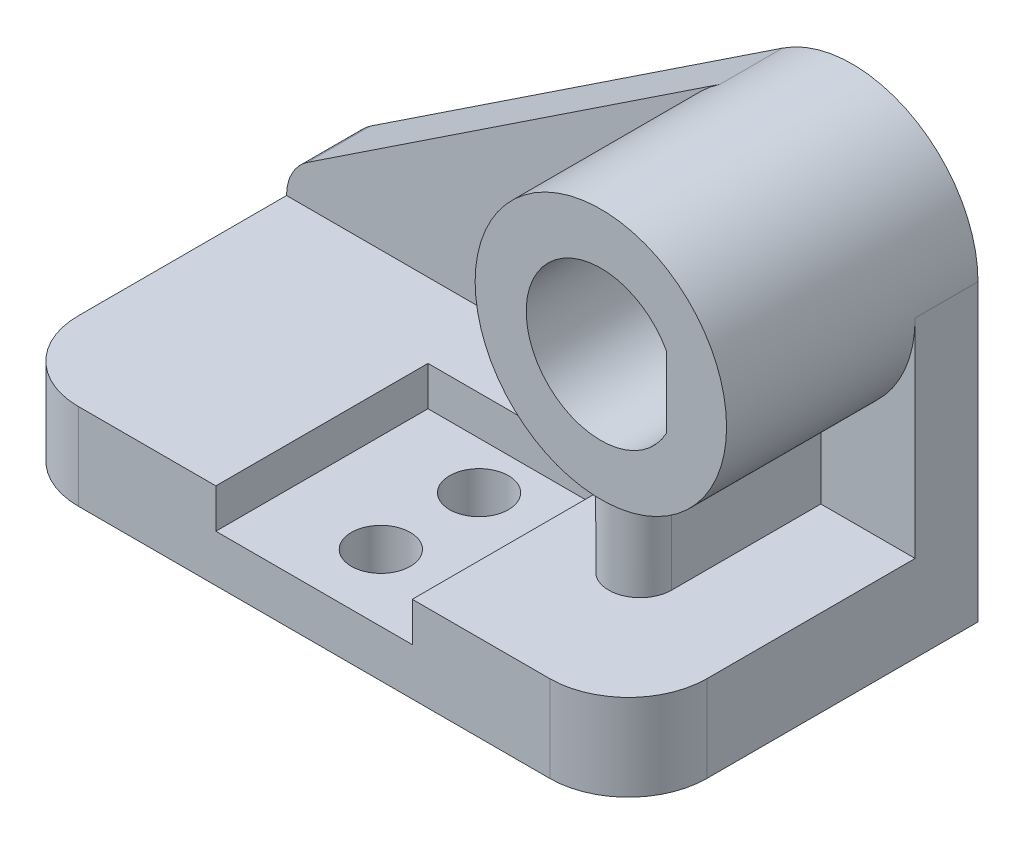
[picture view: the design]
ISO-10303-21;
HEADER;
FILE_DESCRIPTION(('STEP AP214'),'2;1');
FILE_NAME('part.step','',(''),(''),'','','');
FILE_SCHEMA(('AUTOMOTIVE_DESIGN { 1 0 10303 214 1 1 1 1 }'));
ENDSEC;
DATA;
#1=APPLICATION_CONTEXT('core data for automotive mechanical design processes');
#2=APPLICATION_PROTOCOL_DEFINITION('international standard','automotive_design',2000,#1);
#3=PRODUCT_CONTEXT('',#1,'mechanical');
#4=PRODUCT('Part','Part','',(#3));
#5=PRODUCT_RELATED_PRODUCT_CATEGORY('part','',(#4));
#6=PRODUCT_DEFINITION_FORMATION('','',#4);
#7=PRODUCT_DEFINITION_CONTEXT('part definition',#1,'design');
#8=PRODUCT_DEFINITION('design','',#6,#7);
#9=PRODUCT_DEFINITION_SHAPE('','',#8);
#10=(LENGTH_UNIT() NAMED_UNIT(*) SI_UNIT(.MILLI.,.METRE.));
#11=(NAMED_UNIT(*) PLANE_ANGLE_UNIT() SI_UNIT($,.RADIAN.));
#12=(NAMED_UNIT(*) SI_UNIT($,.STERADIAN.) SOLID_ANGLE_UNIT());
#13=UNCERTAINTY_MEASURE_WITH_UNIT(LENGTH_MEASURE(1.E-05),#10,'distance_accuracy_value','');
#14=(GEOMETRIC_REPRESENTATION_CONTEXT(3) GLOBAL_UNCERTAINTY_ASSIGNED_CONTEXT((#13)) GLOBAL_UNIT_ASSIGNED_CONTEXT((#10,
#11,#12)) REPRESENTATION_CONTEXT('',''));
#15=CARTESIAN_POINT('',(0.,0.,0.));
#16=DIRECTION('',(0.,0.,1.));
#17=DIRECTION('',(1.,0.,0.));
#18=AXIS2_PLACEMENT_3D('',#15,#16,#17);
#19=CARTESIAN_POINT('',(128.,75.,-73.));
#20=DIRECTION('',(0.,0.,-1.));
#21=DIRECTION('',(-1.,0.,0.));
#22=AXIS2_PLACEMENT_3D('',#19,#20,#21);
#23=CYLINDRICAL_SURFACE('',#22,32.);
#24=CARTESIAN_POINT('',(128.,75.,-25.));
#25=DIRECTION('',(0.,0.,-1.));
#26=DIRECTION('',(-1.,0.,0.));
#27=AXIS2_PLACEMENT_3D('',#24,#25,#26);
#28=CIRCLE('',#27,32.);
#29=CARTESIAN_POINT('',(96.,75.,-25.));
#30=VERTEX_POINT('',#29);
#31=EDGE_CURVE('E520',#30,#30,#28,.T.);
#32=ORIENTED_EDGE('',*,*,#31,.T.);
#33=EDGE_LOOP('',(#32));
#34=FACE_BOUND('',#33,.T.);
#35=CARTESIAN_POINT('',(128.,75.,-73.));
#36=DIRECTION('',(0.,0.,-1.));
#37=DIRECTION('',(-1.,0.,0.));
#38=AXIS2_PLACEMENT_3D('',#35,#36,#37);
#39=CIRCLE('',#38,32.);
#40=CARTESIAN_POINT('',(120.,44.0161332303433,-73.));
#41=VERTEX_POINT('',#40);
#42=CARTESIAN_POINT('',(110.301754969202,101.660309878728,-73.));
#43=VERTEX_POINT('',#42);
#44=EDGE_CURVE('E500',#41,#43,#39,.T.);
#45=ORIENTED_EDGE('',*,*,#44,.F.);
#46=DIRECTION('',(0.,0.,-1.));
#47=VECTOR('',#46,1.);
#48=CARTESIAN_POINT('',(120.,44.0161332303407,-73.));
#49=LINE('',#48,#47);
#50=CARTESIAN_POINT('',(120.,44.0161332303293,-35.));
#51=VERTEX_POINT('',#50);
#52=EDGE_CURVE('E446',#51,#41,#49,.T.);
#53=ORIENTED_EDGE('',*,*,#52,.F.);
#54=CARTESIAN_POINT('',(136.,44.0161332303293,-35.));
#55=CARTESIAN_POINT('',(136.000028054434,44.0161587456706,-34.7787632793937));
#56=CARTESIAN_POINT('',(135.990823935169,44.0137645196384,-34.5575354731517));
#57=CARTESIAN_POINT('',(135.954157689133,44.0043223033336,-34.1167341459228));
#58=CARTESIAN_POINT('',(135.926698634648,43.9972750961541,-33.897160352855));
#59=CARTESIAN_POINT('',(135.853800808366,43.9787308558,-33.4616585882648));
#60=CARTESIAN_POINT('',(135.808397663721,43.9672426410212,-33.2457242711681));
#61=CARTESIAN_POINT('',(135.699997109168,43.9401676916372,-32.8185811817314));
#62=CARTESIAN_POINT('',(135.636999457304,43.9245809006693,-32.6073724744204));
#63=CARTESIAN_POINT('',(135.493935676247,43.8897712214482,-32.1912044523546));
#64=CARTESIAN_POINT('',(135.413874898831,43.8705494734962,-31.9862432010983));
#65=CARTESIAN_POINT('',(135.237254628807,43.8290139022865,-31.5837954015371));
#66=CARTESIAN_POINT('',(135.140689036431,43.8066989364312,-31.3863116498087));
#67=CARTESIAN_POINT('',(134.931780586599,43.7596114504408,-31.0001741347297));
#68=CARTESIAN_POINT('',(134.81943714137,43.7348388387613,-30.8115207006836));
#69=CARTESIAN_POINT('',(134.579753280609,43.6835209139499,-30.4442414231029));
#70=CARTESIAN_POINT('',(134.452412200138,43.6569755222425,-30.2656160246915));
#71=CARTESIAN_POINT('',(134.180936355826,43.6022999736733,-29.9161090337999));
#72=CARTESIAN_POINT('',(134.036520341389,43.5741489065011,-29.7454491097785));
#73=CARTESIAN_POINT('',(133.733946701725,43.5175360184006,-29.416834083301));
#74=CARTESIAN_POINT('',(133.575788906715,43.4890741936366,-29.2588791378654));
#75=CARTESIAN_POINT('',(133.246739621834,43.4326183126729,-28.956687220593));
#76=CARTESIAN_POINT('',(133.075845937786,43.4046243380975,-28.8124526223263));
#77=CARTESIAN_POINT('',(132.722465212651,43.349877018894,-28.5387095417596));
#78=CARTESIAN_POINT('',(132.539978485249,43.3231236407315,-28.4092006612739));
#79=CARTESIAN_POINT('',(132.161932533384,43.2712239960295,-28.1640813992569));
#80=CARTESIAN_POINT('',(131.966224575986,43.2461059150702,-28.0486942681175));
#81=CARTESIAN_POINT('',(131.56551345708,43.1986195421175,-27.8348995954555));
#82=CARTESIAN_POINT('',(131.360513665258,43.1762502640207,-27.7364859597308));
#83=CARTESIAN_POINT('',(130.942582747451,43.1348890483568,-27.5573596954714));
#84=CARTESIAN_POINT('',(130.729651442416,43.1158971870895,-27.4766474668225));
#85=CARTESIAN_POINT('',(130.297399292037,43.0818398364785,-27.3335941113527));
#86=CARTESIAN_POINT('',(130.078078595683,43.0667742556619,-27.2712525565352));
#87=CARTESIAN_POINT('',(129.639162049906,43.0412689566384,-27.1665450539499));
#88=CARTESIAN_POINT('',(129.419661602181,43.0307417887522,-27.1238003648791));
#89=CARTESIAN_POINT('',(128.977688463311,43.0141746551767,-27.0568218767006));
#90=CARTESIAN_POINT('',(128.755215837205,43.0081345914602,-27.0325876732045));
#91=CARTESIAN_POINT('',(128.308967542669,43.0007135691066,-27.0028417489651));
#92=CARTESIAN_POINT('',(128.085192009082,42.9993321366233,-26.9973281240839));
#93=CARTESIAN_POINT('',(127.637987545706,43.0012665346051,-27.0050667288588));
#94=CARTESIAN_POINT('',(127.414558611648,43.0045823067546,-27.0183187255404));
#95=CARTESIAN_POINT('',(126.974700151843,43.015690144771,-27.0629646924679));
#96=CARTESIAN_POINT('',(126.758225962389,43.0233802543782,-27.0939455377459));
#97=CARTESIAN_POINT('',(126.328649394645,43.04295330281,-27.1734861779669));
#98=CARTESIAN_POINT('',(126.115548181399,43.0548376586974,-27.2220519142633));
#99=CARTESIAN_POINT('',(125.694337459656,43.0824741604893,-27.3363503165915));
#100=CARTESIAN_POINT('',(125.486226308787,43.0982250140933,-27.4020772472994));
#101=CARTESIAN_POINT('',(125.076246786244,43.1331831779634,-27.5502218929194));
#102=CARTESIAN_POINT('',(124.874380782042,43.152391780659,-27.6326458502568));
#103=CARTESIAN_POINT('',(124.476575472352,43.1939341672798,-27.8143399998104));
#104=CARTESIAN_POINT('',(124.280702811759,43.2162936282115,-27.9137501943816));
#105=CARTESIAN_POINT('',(123.897943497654,43.2634227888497,-28.1282260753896));
#106=CARTESIAN_POINT('',(123.71105996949,43.2881933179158,-28.2432971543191));
#107=CARTESIAN_POINT('',(123.347545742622,43.3394825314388,-28.4882640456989));
#108=CARTESIAN_POINT('',(123.170914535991,43.3660011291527,-28.6181591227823));
#109=CARTESIAN_POINT('',(122.828998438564,43.4200901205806,-28.8919145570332));
#110=CARTESIAN_POINT('',(122.663713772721,43.4476605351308,-29.0357751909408));
#111=CARTESIAN_POINT('',(122.34120003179,43.5038811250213,-29.3406231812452));
#112=CARTESIAN_POINT('',(122.184311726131,43.5325402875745,-29.5019696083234));
#113=CARTESIAN_POINT('',(121.884694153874,43.5893921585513,-29.8372902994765));
#114=CARTESIAN_POINT('',(121.741960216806,43.6175850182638,-30.0112603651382));
#115=CARTESIAN_POINT('',(121.471476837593,43.6727362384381,-30.3708496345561));
#116=CARTESIAN_POINT('',(121.343737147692,43.6996937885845,-30.5564763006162));
#117=CARTESIAN_POINT('',(121.104301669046,43.7515704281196,-30.9379756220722));
#118=CARTESIAN_POINT('',(120.99259970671,43.7764903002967,-31.1338442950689));
#119=CARTESIAN_POINT('',(120.78540787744,43.8237105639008,-31.5357441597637));
#120=CARTESIAN_POINT('',(120.690016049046,43.84599488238,-31.7418278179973));
#121=CARTESIAN_POINT('',(120.517029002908,43.8870918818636,-32.1615760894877));
#122=CARTESIAN_POINT('',(120.439426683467,43.9059059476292,-32.3752376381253));
#123=CARTESIAN_POINT('',(120.302684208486,43.9394737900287,-32.8084546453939));
#124=CARTESIAN_POINT('',(120.243524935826,43.9542317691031,-33.0280037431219));
#125=CARTESIAN_POINT('',(120.144091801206,43.979243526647,-33.4714978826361));
#126=CARTESIAN_POINT('',(120.103809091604,43.989499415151,-33.6954408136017));
#127=CARTESIAN_POINT('',(120.048780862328,44.0035684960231,-34.0996119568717));
#128=CARTESIAN_POINT('',(120.030482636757,44.0082740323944,-34.2793341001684));
#129=CARTESIAN_POINT('',(120.006096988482,44.0145591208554,-34.6393658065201));
#130=CARTESIAN_POINT('',(119.99998980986,44.0161437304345,-34.8196739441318));
#131=CARTESIAN_POINT('',(120.,44.0161332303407,-34.9999999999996));
#132=B_SPLINE_CURVE_WITH_KNOTS('',3,(#54,#55,#56,#57,#58,#59,#60,#61,#62,#63,#64,#65,#66,#67,
#68,#69,#70,#71,#72,#73,#74,#75,#76,#77,#78,#79,#80,#81,#82,#83,#84,#85,#86,#87,#88,#89,#90,#91,
#92,#93,#94,#95,#96,#97,#98,#99,#100,#101,#102,#103,#104,#105,#106,#107,#108,#109,#110,#111,
#112,#113,#114,#115,#116,#117,#118,#119,#120,#121,#122,#123,#124,#125,#126,#127,#128,#129,#130,
#131),.UNSPECIFIED.,.F.,.F.,(4,2,2,2,2,2,2,2,2,2,2,2,2,2,2,2,2,2,2,2,2,2,2,2,2,2,2,2,2,2,2,2,2,
2,2,2,2,2,4),(0.,0.66349224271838,1.32687284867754,1.98894290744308,2.65102207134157,
3.31289388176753,3.97501083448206,4.63715245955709,5.29932345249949,5.97452992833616,
6.64974474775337,7.3250761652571,8.00038931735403,8.68528336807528,9.36993099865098,
10.0545940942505,10.7392412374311,11.4100321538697,12.0808084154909,12.7515164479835,
13.4222161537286,14.0778887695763,14.7337831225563,15.3894585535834,16.0453795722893,
16.7069934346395,17.3688356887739,18.0306451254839,18.6924676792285,19.372267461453,
20.0518421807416,20.7318564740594,21.4116082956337,22.0953124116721,22.7787431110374,
23.4614630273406,24.143862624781,24.6855747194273,25.2264082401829),.UNSPECIFIED.);
#133=CARTESIAN_POINT('',(136.,44.0161332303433,-35.));
#134=VERTEX_POINT('',#133);
#135=EDGE_CURVE('E438',#134,#51,#132,.T.);
#136=ORIENTED_EDGE('',*,*,#135,.F.);
#137=DIRECTION('',(0.,0.,-1.));
#138=VECTOR('',#137,1.);
#139=CARTESIAN_POINT('',(136.,44.0161332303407,-73.));
#140=LINE('',#139,#138);
#141=CARTESIAN_POINT('',(136.,44.0161332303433,-73.));
#142=VERTEX_POINT('',#141);
#143=EDGE_CURVE('E436',#142,#134,#140,.F.);
#144=ORIENTED_EDGE('',*,*,#143,.F.);
#145=CARTESIAN_POINT('',(160.,75.,-73.));
#146=VERTEX_POINT('',#145);
#147=EDGE_CURVE('E497',#146,#142,#39,.T.);
#148=ORIENTED_EDGE('',*,*,#147,.F.);
#149=DIRECTION('',(0.,0.,-1.));
#150=VECTOR('',#149,1.);
#151=CARTESIAN_POINT('',(160.,75.,-73.));
#152=LINE('',#151,#150);
#153=CARTESIAN_POINT('',(160.,75.,-89.));
#154=VERTEX_POINT('',#153);
#155=EDGE_CURVE('E11',#146,#154,#152,.T.);
#156=ORIENTED_EDGE('',*,*,#155,.T.);
#157=CARTESIAN_POINT('',(128.,75.,-89.));
#158=DIRECTION('',(0.,0.,-1.));
#159=DIRECTION('',(-1.,0.,0.));
#160=AXIS2_PLACEMENT_3D('',#157,#158,#159);
#161=CIRCLE('',#160,32.);
#162=CARTESIAN_POINT('',(110.301754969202,101.660309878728,-89.));
#163=VERTEX_POINT('',#162);
#164=EDGE_CURVE('E492',#163,#154,#161,.T.);
#165=ORIENTED_EDGE('',*,*,#164,.F.);
#166=DIRECTION('',(0.,0.,-1.));
#167=VECTOR('',#166,1.);
#168=CARTESIAN_POINT('',(110.301754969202,101.660309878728,-73.));
#169=LINE('',#168,#167);
#170=EDGE_CURVE('E43',#43,#163,#169,.T.);
#171=ORIENTED_EDGE('',*,*,#170,.F.);
#172=EDGE_LOOP('',(#45,#53,#136,#144,#148,#156,#165,#171));
#173=FACE_BOUND('',#172,.T.);
#174=ADVANCED_FACE('F34',(#34,#173),#23,.T.);
#175=CARTESIAN_POINT('',(12.,22.,-73.));
#176=DIRECTION('',(0.,0.,-1.));
#177=DIRECTION('',(-1.,0.,0.));
#178=AXIS2_PLACEMENT_3D('',#175,#176,#177);
#179=PLANE('',#178);
#180=DIRECTION('',(0.,-1.,0.));
#181=VECTOR('',#180,1.);
#182=CARTESIAN_POINT('',(120.,500000.,-73.));
#183=LINE('',#182,#181);
#184=CARTESIAN_POINT('',(120.,22.,-73.));
#185=VERTEX_POINT('',#184);
#186=EDGE_CURVE('E434',#41,#185,#183,.T.);
#187=ORIENTED_EDGE('',*,*,#186,.F.);
#188=ORIENTED_EDGE('',*,*,#44,.T.);
#189=DIRECTION('',(0.833134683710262,0.553070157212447,0.));
#190=VECTOR('',#189,1.);
#191=CARTESIAN_POINT('',(5.36315811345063,31.9976162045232,-73.));
#192=LINE('',#191,#190);
#193=CARTESIAN_POINT('',(5.36315811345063,31.9976162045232,-73.));
#194=VERTEX_POINT('',#193);
#195=EDGE_CURVE('E511',#194,#43,#192,.T.);
#196=ORIENTED_EDGE('',*,*,#195,.F.);
#197=CARTESIAN_POINT('',(12.,22.,-73.));
#198=DIRECTION('',(0.,0.,-1.));
#199=DIRECTION('',(-1.,0.,0.));
#200=AXIS2_PLACEMENT_3D('',#197,#198,#199);
#201=CIRCLE('',#200,12.);
#202=CARTESIAN_POINT('',(0.,22.,-73.));
#203=VERTEX_POINT('',#202);
#204=EDGE_CURVE('E515',#203,#194,#201,.T.);
#205=ORIENTED_EDGE('',*,*,#204,.F.);
#206=DIRECTION('',(-1.,0.,0.));
#207=VECTOR('',#206,1.);
#208=CARTESIAN_POINT('',(160.,22.,-73.));
#209=LINE('',#208,#207);
#210=EDGE_CURVE('E508',#185,#203,#209,.T.);
#211=ORIENTED_EDGE('',*,*,#210,.F.);
#212=EDGE_LOOP('',(#187,#188,#196,#205,#211));
#213=FACE_BOUND('',#212,.T.);
#214=ADVANCED_FACE('F461',(#213),#179,.F.);
#215=DIRECTION('',(0.,-1.,0.));
#216=VECTOR('',#215,1.);
#217=CARTESIAN_POINT('',(136.,500000.,-73.));
#218=LINE('',#217,#216);
#219=CARTESIAN_POINT('',(136.,22.,-73.));
#220=VERTEX_POINT('',#219);
#221=EDGE_CURVE('E427',#142,#220,#218,.T.);
#222=ORIENTED_EDGE('',*,*,#221,.T.);
#223=CARTESIAN_POINT('',(160.,22.,-73.));
#224=VERTEX_POINT('',#223);
#225=EDGE_CURVE('E516',#224,#220,#209,.T.);
#226=ORIENTED_EDGE('',*,*,#225,.F.);
#227=DIRECTION('',(0.,-1.,0.));
#228=VECTOR('',#227,1.);
#229=CARTESIAN_POINT('',(160.,22.,-73.));
#230=LINE('',#229,#228);
#231=EDGE_CURVE('E503',#146,#224,#230,.T.);
#232=ORIENTED_EDGE('',*,*,#231,.F.);
#233=ORIENTED_EDGE('',*,*,#147,.T.);
#234=EDGE_LOOP('',(#222,#226,#232,#233));
#235=FACE_BOUND('',#234,.T.);
#236=ADVANCED_FACE('F464',(#235),#179,.F.);
#237=CARTESIAN_POINT('',(160.,22.,-73.));
#238=DIRECTION('',(1.,0.,0.));
#239=DIRECTION('',(0.,1.,0.));
#240=AXIS2_PLACEMENT_3D('',#237,#238,#239);
#241=PLANE('',#240);
#242=DIRECTION('',(0.,-1.,0.));
#243=VECTOR('',#242,1.);
#244=CARTESIAN_POINT('',(160.,22.,-89.));
#245=LINE('',#244,#243);
#246=CARTESIAN_POINT('',(160.,0.,-89.));
#247=VERTEX_POINT('',#246);
#248=EDGE_CURVE('E507',#154,#247,#245,.T.);
#249=ORIENTED_EDGE('',*,*,#248,.F.);
#250=ORIENTED_EDGE('',*,*,#155,.F.);
#251=ORIENTED_EDGE('',*,*,#231,.T.);
#252=DIRECTION('',(0.,0.,-1.));
#253=VECTOR('',#252,1.);
#254=CARTESIAN_POINT('',(160.,22.,-89.));
#255=LINE('',#254,#253);
#256=CARTESIAN_POINT('',(160.,22.,-20.));
#257=VERTEX_POINT('',#256);
#258=EDGE_CURVE('E359',#257,#224,#255,.T.);
#259=ORIENTED_EDGE('',*,*,#258,.F.);
#260=DIRECTION('',(0.,-1.,0.));
#261=VECTOR('',#260,1.);
#262=CARTESIAN_POINT('',(160.,22.,-20.));
#263=LINE('',#262,#261);
#264=CARTESIAN_POINT('',(160.,0.,-20.));
#265=VERTEX_POINT('',#264);
#266=EDGE_CURVE('E383',#257,#265,#263,.T.);
#267=ORIENTED_EDGE('',*,*,#266,.T.);
#268=DIRECTION('',(0.,0.,-1.));
#269=VECTOR('',#268,1.);
#270=CARTESIAN_POINT('',(160.,0.,-89.));
#271=LINE('',#270,#269);
#272=EDGE_CURVE('E353',#265,#247,#271,.T.);
#273=ORIENTED_EDGE('',*,*,#272,.T.);
#274=EDGE_LOOP('',(#249,#250,#251,#259,#267,#273));
#275=FACE_BOUND('',#274,.T.);
#276=ADVANCED_FACE('F469',(#275),#241,.T.);
#277=CARTESIAN_POINT('',(5.36315811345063,31.9976162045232,-73.));
#278=DIRECTION('',(-0.553070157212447,0.833134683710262,0.));
#279=DIRECTION('',(-0.833134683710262,-0.553070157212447,0.));
#280=AXIS2_PLACEMENT_3D('',#277,#278,#279);
#281=PLANE('',#280);
#282=DIRECTION('',(0.833134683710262,0.553070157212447,0.));
#283=VECTOR('',#282,1.);
#284=CARTESIAN_POINT('',(5.36315811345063,31.9976162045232,-89.));
#285=LINE('',#284,#283);
#286=CARTESIAN_POINT('',(5.36315811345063,31.9976162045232,-89.));
#287=VERTEX_POINT('',#286);
#288=EDGE_CURVE('E484',#287,#163,#285,.T.);
#289=ORIENTED_EDGE('',*,*,#288,.F.);
#290=DIRECTION('',(0.,0.,-1.));
#291=VECTOR('',#290,1.);
#292=CARTESIAN_POINT('',(5.36315811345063,31.9976162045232,-73.));
#293=LINE('',#292,#291);
#294=EDGE_CURVE('E38',#194,#287,#293,.T.);
#295=ORIENTED_EDGE('',*,*,#294,.F.);
#296=ORIENTED_EDGE('',*,*,#195,.T.);
#297=ORIENTED_EDGE('',*,*,#170,.T.);
#298=EDGE_LOOP('',(#289,#295,#296,#297));
#299=FACE_BOUND('',#298,.T.);
#300=ADVANCED_FACE('F472',(#299),#281,.T.);
#301=CARTESIAN_POINT('',(12.,22.,-73.));
#302=DIRECTION('',(0.,0.,-1.));
#303=DIRECTION('',(-1.,0.,0.));
#304=AXIS2_PLACEMENT_3D('',#301,#302,#303);
#305=CYLINDRICAL_SURFACE('',#304,12.);
#306=CARTESIAN_POINT('',(12.,22.,-89.));
#307=DIRECTION('',(0.,0.,-1.));
#308=DIRECTION('',(-1.,0.,0.));
#309=AXIS2_PLACEMENT_3D('',#306,#307,#308);
#310=CIRCLE('',#309,12.);
#311=CARTESIAN_POINT('',(0.,22.,-89.));
#312=VERTEX_POINT('',#311);
#313=EDGE_CURVE('E493',#312,#287,#310,.T.);
#314=ORIENTED_EDGE('',*,*,#313,.F.);
#315=DIRECTION('',(0.,0.,1.));
#316=VECTOR('',#315,1.);
#317=CARTESIAN_POINT('',(0.,22.,0.));
#318=LINE('',#317,#316);
#319=EDGE_CURVE('E364',#312,#203,#318,.T.);
#320=ORIENTED_EDGE('',*,*,#319,.T.);
#321=ORIENTED_EDGE('',*,*,#204,.T.);
#322=ORIENTED_EDGE('',*,*,#294,.T.);
#323=EDGE_LOOP('',(#314,#320,#321,#322));
#324=FACE_BOUND('',#323,.T.);
#325=ADVANCED_FACE('F36',(#324),#305,.T.);
#326=CARTESIAN_POINT('',(12.,22.,-89.));
#327=DIRECTION('',(0.,0.,-1.));
#328=DIRECTION('',(-1.,0.,0.));
#329=AXIS2_PLACEMENT_3D('',#326,#327,#328);
#330=PLANE('',#329);
#331=CARTESIAN_POINT('',(128.,75.,-89.));
#332=DIRECTION('',(0.,0.,1.));
#333=DIRECTION('',(1.,0.,0.));
#334=AXIS2_PLACEMENT_3D('',#331,#332,#333);
#335=CIRCLE('',#334,19.);
#336=CARTESIAN_POINT('',(144.733200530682,84.,-89.));
#337=VERTEX_POINT('',#336);
#338=CARTESIAN_POINT('',(144.733200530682,66.,-89.));
#339=VERTEX_POINT('',#338);
#340=EDGE_CURVE('E51',#337,#339,#335,.T.);
#341=ORIENTED_EDGE('',*,*,#340,.T.);
#342=DIRECTION('',(0.,1.,0.));
#343=VECTOR('',#342,1.);
#344=CARTESIAN_POINT('',(144.733200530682,84.,-89.));
#345=LINE('',#344,#343);
#346=EDGE_CURVE('E408',#339,#337,#345,.T.);
#347=ORIENTED_EDGE('',*,*,#346,.T.);
#348=EDGE_LOOP('',(#341,#347));
#349=FACE_BOUND('',#348,.T.);
#350=ORIENTED_EDGE('',*,*,#288,.T.);
#351=ORIENTED_EDGE('',*,*,#164,.T.);
#352=ORIENTED_EDGE('',*,*,#248,.T.);
#353=DIRECTION('',(-1.,0.,0.));
#354=VECTOR('',#353,1.);
#355=CARTESIAN_POINT('',(0.,0.,-89.));
#356=LINE('',#355,#354);
#357=CARTESIAN_POINT('',(0.,0.,-89.));
#358=VERTEX_POINT('',#357);
#359=EDGE_CURVE('E374',#247,#358,#356,.T.);
#360=ORIENTED_EDGE('',*,*,#359,.T.);
#361=DIRECTION('',(0.,-1.,0.));
#362=VECTOR('',#361,1.);
#363=CARTESIAN_POINT('',(0.,22.,-89.));
#364=LINE('',#363,#362);
#365=EDGE_CURVE('E371',#312,#358,#364,.T.);
#366=ORIENTED_EDGE('',*,*,#365,.F.);
#367=ORIENTED_EDGE('',*,*,#313,.T.);
#368=EDGE_LOOP('',(#350,#351,#352,#360,#366,#367));
#369=FACE_BOUND('',#368,.T.);
#370=ADVANCED_FACE('F458',(#349,#369),#330,.T.);
#371=CARTESIAN_POINT('',(128.,75.,-25.));
#372=DIRECTION('',(0.,0.,-1.));
#373=DIRECTION('',(-1.,0.,0.));
#374=AXIS2_PLACEMENT_3D('',#371,#372,#373);
#375=PLANE('',#374);
#376=DIRECTION('',(0.,1.,0.));
#377=VECTOR('',#376,1.);
#378=CARTESIAN_POINT('',(144.733200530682,84.,-25.));
#379=LINE('',#378,#377);
#380=CARTESIAN_POINT('',(144.733200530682,66.,-25.));
#381=VERTEX_POINT('',#380);
#382=CARTESIAN_POINT('',(144.733200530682,84.,-25.));
#383=VERTEX_POINT('',#382);
#384=EDGE_CURVE('E409',#381,#383,#379,.T.);
#385=ORIENTED_EDGE('',*,*,#384,.F.);
#386=CARTESIAN_POINT('',(128.,75.,-25.));
#387=DIRECTION('',(0.,0.,1.));
#388=DIRECTION('',(1.,0.,0.));
#389=AXIS2_PLACEMENT_3D('',#386,#387,#388);
#390=CIRCLE('',#389,19.);
#391=EDGE_CURVE('E56',#383,#381,#390,.T.);
#392=ORIENTED_EDGE('',*,*,#391,.F.);
#393=EDGE_LOOP('',(#385,#392));
#394=FACE_BOUND('',#393,.T.);
#395=ORIENTED_EDGE('',*,*,#31,.F.);
#396=EDGE_LOOP('',(#395));
#397=FACE_BOUND('',#396,.T.);
#398=ADVANCED_FACE('F455',(#394,#397),#375,.F.);
#399=CARTESIAN_POINT('',(120.,500000.,-73.));
#400=DIRECTION('',(1.,0.,0.));
#401=DIRECTION('',(0.,0.,-1.));
#402=AXIS2_PLACEMENT_3D('',#399,#400,#401);
#403=PLANE('',#402);
#404=DIRECTION('',(0.,-1.,0.));
#405=VECTOR('',#404,1.);
#406=CARTESIAN_POINT('',(120.,500000.,-35.));
#407=LINE('',#406,#405);
#408=CARTESIAN_POINT('',(120.,22.,-35.));
#409=VERTEX_POINT('',#408);
#410=EDGE_CURVE('E432',#51,#409,#407,.T.);
#411=ORIENTED_EDGE('',*,*,#410,.F.);
#412=ORIENTED_EDGE('',*,*,#52,.T.);
#413=ORIENTED_EDGE('',*,*,#186,.T.);
#414=DIRECTION('',(0.,0.,1.));
#415=VECTOR('',#414,1.);
#416=CARTESIAN_POINT('',(120.,22.,-73.));
#417=LINE('',#416,#415);
#418=EDGE_CURVE('E418',#185,#409,#417,.T.);
#419=ORIENTED_EDGE('',*,*,#418,.T.);
#420=EDGE_LOOP('',(#411,#412,#413,#419));
#421=FACE_BOUND('',#420,.T.);
#422=ADVANCED_FACE('F454',(#421),#403,.F.);
#423=CARTESIAN_POINT('',(128.,500000.,-35.));
#424=DIRECTION('',(0.,-1.,0.));
#425=DIRECTION('',(0.,0.,-1.));
#426=AXIS2_PLACEMENT_3D('',#423,#424,#425);
#427=CYLINDRICAL_SURFACE('',#426,8.00000000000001);
#428=DIRECTION('',(0.,-1.,0.));
#429=VECTOR('',#428,1.);
#430=CARTESIAN_POINT('',(136.,500000.,-35.));
#431=LINE('',#430,#429);
#432=CARTESIAN_POINT('',(136.,22.,-35.));
#433=VERTEX_POINT('',#432);
#434=EDGE_CURVE('E430',#134,#433,#431,.T.);
#435=ORIENTED_EDGE('',*,*,#434,.F.);
#436=ORIENTED_EDGE('',*,*,#135,.T.);
#437=ORIENTED_EDGE('',*,*,#410,.T.);
#438=CARTESIAN_POINT('',(128.,22.,-35.));
#439=DIRECTION('',(0.,1.,0.));
#440=DIRECTION('',(0.,0.,1.));
#441=AXIS2_PLACEMENT_3D('',#438,#439,#440);
#442=CIRCLE('',#441,8.00000000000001);
#443=EDGE_CURVE('E422',#409,#433,#442,.T.);
#444=ORIENTED_EDGE('',*,*,#443,.T.);
#445=EDGE_LOOP('',(#435,#436,#437,#444));
#446=FACE_BOUND('',#445,.T.);
#447=ADVANCED_FACE('F448',(#446),#427,.T.);
#448=CARTESIAN_POINT('',(136.,500000.,-35.));
#449=DIRECTION('',(-1.,0.,0.));
#450=DIRECTION('',(0.,0.,1.));
#451=AXIS2_PLACEMENT_3D('',#448,#449,#450);
#452=PLANE('',#451);
#453=ORIENTED_EDGE('',*,*,#221,.F.);
#454=ORIENTED_EDGE('',*,*,#143,.T.);
#455=ORIENTED_EDGE('',*,*,#434,.T.);
#456=DIRECTION('',(0.,0.,-1.));
#457=VECTOR('',#456,1.);
#458=CARTESIAN_POINT('',(136.,22.,-35.));
#459=LINE('',#458,#457);
#460=EDGE_CURVE('E425',#433,#220,#459,.T.);
#461=ORIENTED_EDGE('',*,*,#460,.T.);
#462=EDGE_LOOP('',(#453,#454,#455,#461));
#463=FACE_BOUND('',#462,.T.);
#464=ADVANCED_FACE('F460',(#463),#452,.F.);
#465=CARTESIAN_POINT('',(128.,75.,-89.));
#466=DIRECTION('',(0.,0.,1.));
#467=DIRECTION('',(1.,0.,0.));
#468=AXIS2_PLACEMENT_3D('',#465,#466,#467);
#469=CYLINDRICAL_SURFACE('',#468,19.);
#470=ORIENTED_EDGE('',*,*,#391,.T.);
#471=DIRECTION('',(0.,0.,1.));
#472=VECTOR('',#471,1.);
#473=CARTESIAN_POINT('',(144.733200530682,66.,-89.));
#474=LINE('',#473,#472);
#475=EDGE_CURVE('E412',#339,#381,#474,.T.);
#476=ORIENTED_EDGE('',*,*,#475,.F.);
#477=ORIENTED_EDGE('',*,*,#340,.F.);
#478=DIRECTION('',(0.,0.,1.));
#479=VECTOR('',#478,1.);
#480=CARTESIAN_POINT('',(144.733200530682,84.,-89.));
#481=LINE('',#480,#479);
#482=EDGE_CURVE('E416',#337,#383,#481,.T.);
#483=ORIENTED_EDGE('',*,*,#482,.T.);
#484=EDGE_LOOP('',(#470,#476,#477,#483));
#485=FACE_BOUND('',#484,.T.);
#486=ADVANCED_FACE('F612',(#485),#469,.F.);
#487=CARTESIAN_POINT('',(144.733200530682,84.,-89.));
#488=DIRECTION('',(1.,0.,0.));
#489=DIRECTION('',(0.,0.,-1.));
#490=AXIS2_PLACEMENT_3D('',#487,#488,#489);
#491=PLANE('',#490);
#492=ORIENTED_EDGE('',*,*,#384,.T.);
#493=ORIENTED_EDGE('',*,*,#482,.F.);
#494=ORIENTED_EDGE('',*,*,#346,.F.);
#495=ORIENTED_EDGE('',*,*,#475,.T.);
#496=EDGE_LOOP('',(#492,#493,#494,#495));
#497=FACE_BOUND('',#496,.T.);
#498=ADVANCED_FACE('F609',(#497),#491,.F.);
#499=CARTESIAN_POINT('',(0.,0.,0.));
#500=DIRECTION('',(0.,1.,0.));
#501=DIRECTION('',(0.,0.,1.));
#502=AXIS2_PLACEMENT_3D('',#499,#500,#501);
#503=PLANE('',#502);
#504=CARTESIAN_POINT('',(80.,0.,-17.));
#505=DIRECTION('',(0.,1.,0.));
#506=DIRECTION('',(0.,0.,1.));
#507=AXIS2_PLACEMENT_3D('',#504,#505,#506);
#508=CIRCLE('',#507,7.5);
#509=CARTESIAN_POINT('',(80.,0.,-9.50000000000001));
#510=VERTEX_POINT('',#509);
#511=EDGE_CURVE('E323',#510,#510,#508,.T.);
#512=ORIENTED_EDGE('',*,*,#511,.T.);
#513=EDGE_LOOP('',(#512));
#514=FACE_BOUND('',#513,.T.);
#515=CARTESIAN_POINT('',(80.,0.,-17.));
#516=DIRECTION('',(0.,1.,0.));
#517=DIRECTION('',(0.,0.,1.));
#518=AXIS2_PLACEMENT_3D('',#515,#516,#517);
#519=CIRCLE('',#518,11.5);
#520=CARTESIAN_POINT('',(80.,0.,-5.50000000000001));
#521=VERTEX_POINT('',#520);
#522=EDGE_CURVE('E303',#521,#521,#519,.T.);
#523=ORIENTED_EDGE('',*,*,#522,.F.);
#524=EDGE_LOOP('',(#523));
#525=FACE_BOUND('',#524,.T.);
#526=ADVANCED_FACE('F599',(#514,#525),#503,.F.);
#527=CARTESIAN_POINT('',(80.,0.,-42.));
#528=DIRECTION('',(0.,1.,0.));
#529=DIRECTION('',(0.,0.,1.));
#530=AXIS2_PLACEMENT_3D('',#527,#528,#529);
#531=CIRCLE('',#530,7.5);
#532=CARTESIAN_POINT('',(80.,0.,-34.5));
#533=VERTEX_POINT('',#532);
#534=EDGE_CURVE('E292',#533,#533,#531,.T.);
#535=ORIENTED_EDGE('',*,*,#534,.T.);
#536=EDGE_LOOP('',(#535));
#537=FACE_BOUND('',#536,.T.);
#538=CARTESIAN_POINT('',(80.,0.,-42.));
#539=DIRECTION('',(0.,1.,0.));
#540=DIRECTION('',(0.,0.,1.));
#541=AXIS2_PLACEMENT_3D('',#538,#539,#540);
#542=CIRCLE('',#541,11.5);
#543=CARTESIAN_POINT('',(80.,0.,-30.5));
#544=VERTEX_POINT('',#543);
#545=EDGE_CURVE('E318',#544,#544,#542,.T.);
#546=ORIENTED_EDGE('',*,*,#545,.F.);
#547=EDGE_LOOP('',(#546));
#548=FACE_BOUND('',#547,.T.);
#549=ADVANCED_FACE('F600',(#537,#548),#503,.F.);
#550=CARTESIAN_POINT('',(0.,22.,0.));
#551=DIRECTION('',(0.,0.,-1.));
#552=DIRECTION('',(-1.,0.,0.));
#553=AXIS2_PLACEMENT_3D('',#550,#551,#552);
#554=PLANE('',#553);
#555=DIRECTION('',(0.,1.,0.));
#556=VECTOR('',#555,1.);
#557=CARTESIAN_POINT('',(55.,12.,0.));
#558=LINE('',#557,#556);
#559=CARTESIAN_POINT('',(55.,12.,0.));
#560=VERTEX_POINT('',#559);
#561=CARTESIAN_POINT('',(55.,22.,0.));
#562=VERTEX_POINT('',#561);
#563=EDGE_CURVE('E350',#560,#562,#558,.T.);
#564=ORIENTED_EDGE('',*,*,#563,.T.);
#565=DIRECTION('',(1.,0.,0.));
#566=VECTOR('',#565,1.);
#567=CARTESIAN_POINT('',(0.,22.,0.));
#568=LINE('',#567,#566);
#569=CARTESIAN_POINT('',(20.,22.,0.));
#570=VERTEX_POINT('',#569);
#571=EDGE_CURVE('E368',#570,#562,#568,.T.);
#572=ORIENTED_EDGE('',*,*,#571,.F.);
#573=DIRECTION('',(0.,-1.,0.));
#574=VECTOR('',#573,1.);
#575=CARTESIAN_POINT('',(20.,22.,0.));
#576=LINE('',#575,#574);
#577=CARTESIAN_POINT('',(20.,0.,0.));
#578=VERTEX_POINT('',#577);
#579=EDGE_CURVE('E390',#570,#578,#576,.T.);
#580=ORIENTED_EDGE('',*,*,#579,.T.);
#581=DIRECTION('',(1.,0.,0.));
#582=VECTOR('',#581,1.);
#583=CARTESIAN_POINT('',(0.,0.,0.));
#584=LINE('',#583,#582);
#585=CARTESIAN_POINT('',(140.,0.,0.));
#586=VERTEX_POINT('',#585);
#587=EDGE_CURVE('E363',#578,#586,#584,.T.);
#588=ORIENTED_EDGE('',*,*,#587,.T.);
#589=DIRECTION('',(0.,-1.,0.));
#590=VECTOR('',#589,1.);
#591=CARTESIAN_POINT('',(140.,22.,0.));
#592=LINE('',#591,#590);
#593=CARTESIAN_POINT('',(140.,22.,0.));
#594=VERTEX_POINT('',#593);
#595=EDGE_CURVE('E393',#586,#594,#592,.F.);
#596=ORIENTED_EDGE('',*,*,#595,.T.);
#597=CARTESIAN_POINT('',(105.,22.,0.));
#598=VERTEX_POINT('',#597);
#599=EDGE_CURVE('E367',#598,#594,#568,.T.);
#600=ORIENTED_EDGE('',*,*,#599,.F.);
#601=DIRECTION('',(0.,1.,0.));
#602=VECTOR('',#601,1.);
#603=CARTESIAN_POINT('',(105.,12.,0.));
#604=LINE('',#603,#602);
#605=CARTESIAN_POINT('',(105.,12.,0.));
#606=VERTEX_POINT('',#605);
#607=EDGE_CURVE('E340',#606,#598,#604,.T.);
#608=ORIENTED_EDGE('',*,*,#607,.F.);
#609=DIRECTION('',(1.,0.,0.));
#610=VECTOR('',#609,1.);
#611=CARTESIAN_POINT('',(55.,12.,0.));
#612=LINE('',#611,#610);
#613=EDGE_CURVE('E329',#560,#606,#612,.T.);
#614=ORIENTED_EDGE('',*,*,#613,.F.);
#615=EDGE_LOOP('',(#564,#572,#580,#588,#596,#600,#608,#614));
#616=FACE_BOUND('',#615,.T.);
#617=ADVANCED_FACE('F559',(#616),#554,.F.);
#618=CARTESIAN_POINT('',(0.,22.,0.));
#619=DIRECTION('',(0.,1.,0.));
#620=DIRECTION('',(0.,0.,1.));
#621=AXIS2_PLACEMENT_3D('',#618,#619,#620);
#622=PLANE('',#621);
#623=ORIENTED_EDGE('',*,*,#258,.T.);
#624=ORIENTED_EDGE('',*,*,#225,.T.);
#625=ORIENTED_EDGE('',*,*,#460,.F.);
#626=ORIENTED_EDGE('',*,*,#443,.F.);
#627=ORIENTED_EDGE('',*,*,#418,.F.);
#628=ORIENTED_EDGE('',*,*,#210,.T.);
#629=CARTESIAN_POINT('',(0.,22.,-20.));
#630=VERTEX_POINT('',#629);
#631=EDGE_CURVE('E362',#203,#630,#318,.T.);
#632=ORIENTED_EDGE('',*,*,#631,.T.);
#633=CARTESIAN_POINT('',(20.,22.,-20.));
#634=DIRECTION('',(0.,1.,0.));
#635=DIRECTION('',(0.,0.,1.));
#636=AXIS2_PLACEMENT_3D('',#633,#634,#635);
#637=CIRCLE('',#636,20.);
#638=EDGE_CURVE('E396',#630,#570,#637,.T.);
#639=ORIENTED_EDGE('',*,*,#638,.T.);
#640=ORIENTED_EDGE('',*,*,#571,.T.);
#641=DIRECTION('',(0.,0.,-1.));
#642=VECTOR('',#641,1.);
#643=CARTESIAN_POINT('',(55.,22.,0.));
#644=LINE('',#643,#642);
#645=CARTESIAN_POINT('',(55.,22.,-54.));
#646=VERTEX_POINT('',#645);
#647=EDGE_CURVE('E333',#562,#646,#644,.T.);
#648=ORIENTED_EDGE('',*,*,#647,.T.);
#649=DIRECTION('',(1.,0.,0.));
#650=VECTOR('',#649,1.);
#651=CARTESIAN_POINT('',(55.,22.,-54.));
#652=LINE('',#651,#650);
#653=CARTESIAN_POINT('',(105.,22.,-54.));
#654=VERTEX_POINT('',#653);
#655=EDGE_CURVE('E344',#646,#654,#652,.T.);
#656=ORIENTED_EDGE('',*,*,#655,.T.);
#657=DIRECTION('',(0.,0.,-1.));
#658=VECTOR('',#657,1.);
#659=CARTESIAN_POINT('',(105.,22.,0.));
#660=LINE('',#659,#658);
#661=EDGE_CURVE('E341',#598,#654,#660,.T.);
#662=ORIENTED_EDGE('',*,*,#661,.F.);
#663=ORIENTED_EDGE('',*,*,#599,.T.);
#664=CARTESIAN_POINT('',(140.,22.,-20.));
#665=DIRECTION('',(0.,1.,0.));
#666=DIRECTION('',(0.,0.,1.));
#667=AXIS2_PLACEMENT_3D('',#664,#665,#666);
#668=CIRCLE('',#667,20.);
#669=EDGE_CURVE('E398',#594,#257,#668,.T.);
#670=ORIENTED_EDGE('',*,*,#669,.T.);
#671=EDGE_LOOP('',(#623,#624,#625,#626,#627,#628,#632,#639,#640,#648,#656,#662,#663,#670));
#672=FACE_BOUND('',#671,.T.);
#673=ADVANCED_FACE('F545',(#672),#622,.T.);
#674=CARTESIAN_POINT('',(0.,22.,0.));
#675=DIRECTION('',(1.,0.,0.));
#676=DIRECTION('',(0.,0.,-1.));
#677=AXIS2_PLACEMENT_3D('',#674,#675,#676);
#678=PLANE('',#677);
#679=DIRECTION('',(0.,0.,1.));
#680=VECTOR('',#679,1.);
#681=CARTESIAN_POINT('',(0.,0.,0.));
#682=LINE('',#681,#680);
#683=CARTESIAN_POINT('',(0.,0.,-20.));
#684=VERTEX_POINT('',#683);
#685=EDGE_CURVE('E376',#358,#684,#682,.T.);
#686=ORIENTED_EDGE('',*,*,#685,.T.);
#687=DIRECTION('',(0.,-1.,0.));
#688=VECTOR('',#687,1.);
#689=CARTESIAN_POINT('',(0.,22.,-20.));
#690=LINE('',#689,#688);
#691=EDGE_CURVE('E400',#684,#630,#690,.F.);
#692=ORIENTED_EDGE('',*,*,#691,.T.);
#693=ORIENTED_EDGE('',*,*,#631,.F.);
#694=ORIENTED_EDGE('',*,*,#319,.F.);
#695=ORIENTED_EDGE('',*,*,#365,.T.);
#696=EDGE_LOOP('',(#686,#692,#693,#694,#695));
#697=FACE_BOUND('',#696,.T.);
#698=ADVANCED_FACE('F541',(#697),#678,.F.);
#699=CARTESIAN_POINT('',(140.,0.,-20.));
#700=DIRECTION('',(0.,1.,0.));
#701=DIRECTION('',(0.,0.,1.));
#702=AXIS2_PLACEMENT_3D('',#699,#700,#701);
#703=CIRCLE('',#702,16.);
#704=CARTESIAN_POINT('',(156.,0.,-20.));
#705=VERTEX_POINT('',#704);
#706=CARTESIAN_POINT('',(140.,0.,-4.));
#707=VERTEX_POINT('',#706);
#708=EDGE_CURVE('E308',#705,#707,#703,.F.);
#709=ORIENTED_EDGE('',*,*,#708,.F.);
#710=DIRECTION('',(0.,0.,-1.));
#711=VECTOR('',#710,1.);
#712=CARTESIAN_POINT('',(156.,0.,-89.));
#713=LINE('',#712,#711);
#714=CARTESIAN_POINT('',(156.,0.,-85.));
#715=VERTEX_POINT('',#714);
#716=EDGE_CURVE('E240',#705,#715,#713,.T.);
#717=ORIENTED_EDGE('',*,*,#716,.T.);
#718=DIRECTION('',(-1.,0.,0.));
#719=VECTOR('',#718,1.);
#720=CARTESIAN_POINT('',(0.,0.,-85.));
#721=LINE('',#720,#719);
#722=CARTESIAN_POINT('',(4.,0.,-85.));
#723=VERTEX_POINT('',#722);
#724=EDGE_CURVE('E311',#715,#723,#721,.T.);
#725=ORIENTED_EDGE('',*,*,#724,.T.);
#726=DIRECTION('',(0.,0.,1.));
#727=VECTOR('',#726,1.);
#728=CARTESIAN_POINT('',(4.,0.,0.));
#729=LINE('',#728,#727);
#730=CARTESIAN_POINT('',(4.,0.,-20.));
#731=VERTEX_POINT('',#730);
#732=EDGE_CURVE('E306',#723,#731,#729,.T.);
#733=ORIENTED_EDGE('',*,*,#732,.T.);
#734=CARTESIAN_POINT('',(20.,0.,-20.));
#735=DIRECTION('',(0.,1.,0.));
#736=DIRECTION('',(0.,0.,1.));
#737=AXIS2_PLACEMENT_3D('',#734,#735,#736);
#738=CIRCLE('',#737,16.);
#739=CARTESIAN_POINT('',(20.,0.,-4.));
#740=VERTEX_POINT('',#739);
#741=EDGE_CURVE('E285',#740,#731,#738,.F.);
#742=ORIENTED_EDGE('',*,*,#741,.F.);
#743=DIRECTION('',(1.,0.,0.));
#744=VECTOR('',#743,1.);
#745=CARTESIAN_POINT('',(0.,0.,-4.));
#746=LINE('',#745,#744);
#747=EDGE_CURVE('E275',#740,#707,#746,.T.);
#748=ORIENTED_EDGE('',*,*,#747,.T.);
#749=EDGE_LOOP('',(#709,#717,#725,#733,#742,#748));
#750=FACE_BOUND('',#749,.T.);
#751=ORIENTED_EDGE('',*,*,#272,.F.);
#752=CARTESIAN_POINT('',(140.,0.,-20.));
#753=DIRECTION('',(0.,1.,0.));
#754=DIRECTION('',(0.,0.,1.));
#755=AXIS2_PLACEMENT_3D('',#752,#753,#754);
#756=CIRCLE('',#755,20.);
#757=EDGE_CURVE('E388',#265,#586,#756,.F.);
#758=ORIENTED_EDGE('',*,*,#757,.T.);
#759=ORIENTED_EDGE('',*,*,#587,.F.);
#760=CARTESIAN_POINT('',(20.,0.,-20.));
#761=DIRECTION('',(0.,1.,0.));
#762=DIRECTION('',(0.,0.,1.));
#763=AXIS2_PLACEMENT_3D('',#760,#761,#762);
#764=CIRCLE('',#763,20.);
#765=EDGE_CURVE('E386',#578,#684,#764,.F.);
#766=ORIENTED_EDGE('',*,*,#765,.T.);
#767=ORIENTED_EDGE('',*,*,#685,.F.);
#768=ORIENTED_EDGE('',*,*,#359,.F.);
#769=EDGE_LOOP('',(#751,#758,#759,#766,#767,#768));
#770=FACE_BOUND('',#769,.T.);
#771=ADVANCED_FACE('F539',(#750,#770),#503,.F.);
#772=CARTESIAN_POINT('',(140.,22.,-20.));
#773=DIRECTION('',(0.,-1.,0.));
#774=DIRECTION('',(0.,0.,-1.));
#775=AXIS2_PLACEMENT_3D('',#772,#773,#774);
#776=CYLINDRICAL_SURFACE('',#775,20.);
#777=ORIENTED_EDGE('',*,*,#669,.F.);
#778=ORIENTED_EDGE('',*,*,#595,.F.);
#779=ORIENTED_EDGE('',*,*,#757,.F.);
#780=ORIENTED_EDGE('',*,*,#266,.F.);
#781=EDGE_LOOP('',(#777,#778,#779,#780));
#782=FACE_BOUND('',#781,.T.);
#783=ADVANCED_FACE('F555',(#782),#776,.T.);
#784=CARTESIAN_POINT('',(20.,22.,-20.));
#785=DIRECTION('',(0.,-1.,0.));
#786=DIRECTION('',(0.,0.,-1.));
#787=AXIS2_PLACEMENT_3D('',#784,#785,#786);
#788=CYLINDRICAL_SURFACE('',#787,20.);
#789=ORIENTED_EDGE('',*,*,#638,.F.);
#790=ORIENTED_EDGE('',*,*,#691,.F.);
#791=ORIENTED_EDGE('',*,*,#765,.F.);
#792=ORIENTED_EDGE('',*,*,#579,.F.);
#793=EDGE_LOOP('',(#789,#790,#791,#792));
#794=FACE_BOUND('',#793,.T.);
#795=ADVANCED_FACE('F565',(#794),#788,.T.);
#796=CARTESIAN_POINT('',(55.,12.,0.));
#797=DIRECTION('',(1.,0.,0.));
#798=DIRECTION('',(0.,0.,-1.));
#799=AXIS2_PLACEMENT_3D('',#796,#797,#798);
#800=PLANE('',#799);
#801=ORIENTED_EDGE('',*,*,#647,.F.);
#802=ORIENTED_EDGE('',*,*,#563,.F.);
#803=DIRECTION('',(0.,0.,-1.));
#804=VECTOR('',#803,1.);
#805=CARTESIAN_POINT('',(55.,12.,0.));
#806=LINE('',#805,#804);
#807=CARTESIAN_POINT('',(55.,12.,-54.));
#808=VERTEX_POINT('',#807);
#809=EDGE_CURVE('E338',#560,#808,#806,.T.);
#810=ORIENTED_EDGE('',*,*,#809,.T.);
#811=DIRECTION('',(0.,1.,0.));
#812=VECTOR('',#811,1.);
#813=CARTESIAN_POINT('',(55.,12.,-54.));
#814=LINE('',#813,#812);
#815=EDGE_CURVE('E354',#808,#646,#814,.T.);
#816=ORIENTED_EDGE('',*,*,#815,.T.);
#817=EDGE_LOOP('',(#801,#802,#810,#816));
#818=FACE_BOUND('',#817,.T.);
#819=ADVANCED_FACE('F569',(#818),#800,.T.);
#820=CARTESIAN_POINT('',(55.,12.,-54.));
#821=DIRECTION('',(0.,0.,1.));
#822=DIRECTION('',(1.,0.,0.));
#823=AXIS2_PLACEMENT_3D('',#820,#821,#822);
#824=PLANE('',#823);
#825=ORIENTED_EDGE('',*,*,#655,.F.);
#826=ORIENTED_EDGE('',*,*,#815,.F.);
#827=DIRECTION('',(1.,0.,0.));
#828=VECTOR('',#827,1.);
#829=CARTESIAN_POINT('',(55.,12.,-54.));
#830=LINE('',#829,#828);
#831=CARTESIAN_POINT('',(105.,12.,-54.));
#832=VERTEX_POINT('',#831);
#833=EDGE_CURVE('E336',#808,#832,#830,.T.);
#834=ORIENTED_EDGE('',*,*,#833,.T.);
#835=DIRECTION('',(0.,1.,0.));
#836=VECTOR('',#835,1.);
#837=CARTESIAN_POINT('',(105.,12.,-54.));
#838=LINE('',#837,#836);
#839=EDGE_CURVE('E356',#832,#654,#838,.T.);
#840=ORIENTED_EDGE('',*,*,#839,.T.);
#841=EDGE_LOOP('',(#825,#826,#834,#840));
#842=FACE_BOUND('',#841,.T.);
#843=ADVANCED_FACE('F578',(#842),#824,.T.);
#844=CARTESIAN_POINT('',(105.,12.,0.));
#845=DIRECTION('',(1.,0.,0.));
#846=DIRECTION('',(0.,0.,-1.));
#847=AXIS2_PLACEMENT_3D('',#844,#845,#846);
#848=PLANE('',#847);
#849=ORIENTED_EDGE('',*,*,#661,.T.);
#850=ORIENTED_EDGE('',*,*,#839,.F.);
#851=DIRECTION('',(0.,0.,-1.));
#852=VECTOR('',#851,1.);
#853=CARTESIAN_POINT('',(105.,12.,0.));
#854=LINE('',#853,#852);
#855=EDGE_CURVE('E332',#606,#832,#854,.T.);
#856=ORIENTED_EDGE('',*,*,#855,.F.);
#857=ORIENTED_EDGE('',*,*,#607,.T.);
#858=EDGE_LOOP('',(#849,#850,#856,#857));
#859=FACE_BOUND('',#858,.T.);
#860=ADVANCED_FACE('F581',(#859),#848,.F.);
#861=CARTESIAN_POINT('',(0.,12.,0.));
#862=DIRECTION('',(0.,1.,0.));
#863=DIRECTION('',(0.,0.,1.));
#864=AXIS2_PLACEMENT_3D('',#861,#862,#863);
#865=PLANE('',#864);
#866=CARTESIAN_POINT('',(80.,12.,-17.));
#867=DIRECTION('',(0.,1.,0.));
#868=DIRECTION('',(0.,0.,1.));
#869=AXIS2_PLACEMENT_3D('',#866,#867,#868);
#870=CIRCLE('',#869,7.5);
#871=CARTESIAN_POINT('',(80.,12.,-9.50000000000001));
#872=VERTEX_POINT('',#871);
#873=EDGE_CURVE('E345',#872,#872,#870,.T.);
#874=ORIENTED_EDGE('',*,*,#873,.F.);
#875=EDGE_LOOP('',(#874));
#876=FACE_BOUND('',#875,.T.);
#877=CARTESIAN_POINT('',(80.,12.,-42.));
#878=DIRECTION('',(0.,1.,0.));
#879=DIRECTION('',(0.,0.,1.));
#880=AXIS2_PLACEMENT_3D('',#877,#878,#879);
#881=CIRCLE('',#880,7.5);
#882=CARTESIAN_POINT('',(80.,12.,-34.5));
#883=VERTEX_POINT('',#882);
#884=EDGE_CURVE('E326',#883,#883,#881,.T.);
#885=ORIENTED_EDGE('',*,*,#884,.F.);
#886=EDGE_LOOP('',(#885));
#887=FACE_BOUND('',#886,.T.);
#888=ORIENTED_EDGE('',*,*,#613,.T.);
#889=ORIENTED_EDGE('',*,*,#855,.T.);
#890=ORIENTED_EDGE('',*,*,#833,.F.);
#891=ORIENTED_EDGE('',*,*,#809,.F.);
#892=EDGE_LOOP('',(#888,#889,#890,#891));
#893=FACE_BOUND('',#892,.T.);
#894=ADVANCED_FACE('F575',(#876,#887,#893),#865,.T.);
#895=CARTESIAN_POINT('',(80.,0.,-42.));
#896=DIRECTION('',(0.,1.,0.));
#897=DIRECTION('',(0.,0.,1.));
#898=AXIS2_PLACEMENT_3D('',#895,#896,#897);
#899=CYLINDRICAL_SURFACE('',#898,7.5);
#900=ORIENTED_EDGE('',*,*,#884,.T.);
#901=EDGE_LOOP('',(#900));
#902=FACE_BOUND('',#901,.T.);
#903=ORIENTED_EDGE('',*,*,#534,.F.);
#904=EDGE_LOOP('',(#903));
#905=FACE_BOUND('',#904,.T.);
#906=ADVANCED_FACE('F588',(#902,#905),#899,.F.);
#907=CARTESIAN_POINT('',(80.,0.,-17.));
#908=DIRECTION('',(0.,1.,0.));
#909=DIRECTION('',(0.,0.,1.));
#910=AXIS2_PLACEMENT_3D('',#907,#908,#909);
#911=CYLINDRICAL_SURFACE('',#910,7.5);
#912=ORIENTED_EDGE('',*,*,#873,.T.);
#913=EDGE_LOOP('',(#912));
#914=FACE_BOUND('',#913,.T.);
#915=ORIENTED_EDGE('',*,*,#511,.F.);
#916=EDGE_LOOP('',(#915));
#917=FACE_BOUND('',#916,.T.);
#918=ADVANCED_FACE('F779',(#914,#917),#911,.F.);
#919=CARTESIAN_POINT('',(0.,22.,-4.));
#920=DIRECTION('',(0.,0.,-1.));
#921=DIRECTION('',(-1.,0.,0.));
#922=AXIS2_PLACEMENT_3D('',#919,#920,#921);
#923=PLANE('',#922);
#924=DIRECTION('',(0.,1.,0.));
#925=VECTOR('',#924,1.);
#926=CARTESIAN_POINT('',(51.,12.,-4.));
#927=LINE('',#926,#925);
#928=CARTESIAN_POINT('',(51.,8.,-4.));
#929=VERTEX_POINT('',#928);
#930=CARTESIAN_POINT('',(51.,18.,-4.));
#931=VERTEX_POINT('',#930);
#932=EDGE_CURVE('E229',#929,#931,#927,.T.);
#933=ORIENTED_EDGE('',*,*,#932,.F.);
#934=DIRECTION('',(1.,0.,0.));
#935=VECTOR('',#934,1.);
#936=CARTESIAN_POINT('',(0.,8.,-4.));
#937=LINE('',#936,#935);
#938=CARTESIAN_POINT('',(109.,8.,-4.));
#939=VERTEX_POINT('',#938);
#940=EDGE_CURVE('E233',#929,#939,#937,.T.);
#941=ORIENTED_EDGE('',*,*,#940,.T.);
#942=DIRECTION('',(0.,1.,0.));
#943=VECTOR('',#942,1.);
#944=CARTESIAN_POINT('',(109.,12.,-4.));
#945=LINE('',#944,#943);
#946=CARTESIAN_POINT('',(109.,18.,-4.));
#947=VERTEX_POINT('',#946);
#948=EDGE_CURVE('E248',#939,#947,#945,.T.);
#949=ORIENTED_EDGE('',*,*,#948,.T.);
#950=DIRECTION('',(1.,0.,0.));
#951=VECTOR('',#950,1.);
#952=CARTESIAN_POINT('',(0.,18.,-4.));
#953=LINE('',#952,#951);
#954=CARTESIAN_POINT('',(140.,18.,-4.));
#955=VERTEX_POINT('',#954);
#956=EDGE_CURVE('E280',#947,#955,#953,.T.);
#957=ORIENTED_EDGE('',*,*,#956,.T.);
#958=DIRECTION('',(0.,1.,0.));
#959=VECTOR('',#958,1.);
#960=CARTESIAN_POINT('',(140.,22.,-4.));
#961=LINE('',#960,#959);
#962=EDGE_CURVE('E282',#707,#955,#961,.T.);
#963=ORIENTED_EDGE('',*,*,#962,.F.);
#964=ORIENTED_EDGE('',*,*,#747,.F.);
#965=DIRECTION('',(0.,1.,0.));
#966=VECTOR('',#965,1.);
#967=CARTESIAN_POINT('',(20.,22.,-4.));
#968=LINE('',#967,#966);
#969=CARTESIAN_POINT('',(20.,18.,-4.));
#970=VERTEX_POINT('',#969);
#971=EDGE_CURVE('E317',#970,#740,#968,.F.);
#972=ORIENTED_EDGE('',*,*,#971,.F.);
#973=DIRECTION('',(1.,0.,0.));
#974=VECTOR('',#973,1.);
#975=CARTESIAN_POINT('',(0.,18.,-4.));
#976=LINE('',#975,#974);
#977=EDGE_CURVE('E237',#970,#931,#976,.T.);
#978=ORIENTED_EDGE('',*,*,#977,.T.);
#979=EDGE_LOOP('',(#933,#941,#949,#957,#963,#964,#972,#978));
#980=FACE_BOUND('',#979,.T.);
#981=ADVANCED_FACE('F231',(#980),#923,.T.);
#982=CARTESIAN_POINT('',(0.,18.,0.));
#983=DIRECTION('',(0.,1.,0.));
#984=DIRECTION('',(0.,0.,1.));
#985=AXIS2_PLACEMENT_3D('',#982,#983,#984);
#986=PLANE('',#985);
#987=ORIENTED_EDGE('',*,*,#977,.F.);
#988=CARTESIAN_POINT('',(20.,18.,-20.));
#989=DIRECTION('',(0.,1.,0.));
#990=DIRECTION('',(0.,0.,1.));
#991=AXIS2_PLACEMENT_3D('',#988,#989,#990);
#992=CIRCLE('',#991,16.);
#993=CARTESIAN_POINT('',(4.,18.,-20.));
#994=VERTEX_POINT('',#993);
#995=EDGE_CURVE('E271',#994,#970,#992,.T.);
#996=ORIENTED_EDGE('',*,*,#995,.F.);
#997=DIRECTION('',(0.,0.,1.));
#998=VECTOR('',#997,1.);
#999=CARTESIAN_POINT('',(4.,18.,0.));
#1000=LINE('',#999,#998);
#1001=CARTESIAN_POINT('',(4.,18.,-85.));
#1002=VERTEX_POINT('',#1001);
#1003=EDGE_CURVE('E277',#1002,#994,#1000,.T.);
#1004=ORIENTED_EDGE('',*,*,#1003,.F.);
#1005=DIRECTION('',(-1.,0.,0.));
#1006=VECTOR('',#1005,1.);
#1007=CARTESIAN_POINT('',(0.,18.,-85.));
#1008=LINE('',#1007,#1006);
#1009=CARTESIAN_POINT('',(156.,18.,-85.));
#1010=VERTEX_POINT('',#1009);
#1011=EDGE_CURVE('E274',#1010,#1002,#1008,.T.);
#1012=ORIENTED_EDGE('',*,*,#1011,.F.);
#1013=DIRECTION('',(0.,0.,-1.));
#1014=VECTOR('',#1013,1.);
#1015=CARTESIAN_POINT('',(156.,18.,-89.));
#1016=LINE('',#1015,#1014);
#1017=CARTESIAN_POINT('',(156.,18.,-20.));
#1018=VERTEX_POINT('',#1017);
#1019=EDGE_CURVE('E272',#1018,#1010,#1016,.T.);
#1020=ORIENTED_EDGE('',*,*,#1019,.F.);
#1021=CARTESIAN_POINT('',(140.,18.,-20.));
#1022=DIRECTION('',(0.,1.,0.));
#1023=DIRECTION('',(0.,0.,1.));
#1024=AXIS2_PLACEMENT_3D('',#1021,#1022,#1023);
#1025=CIRCLE('',#1024,16.);
#1026=EDGE_CURVE('E268',#955,#1018,#1025,.T.);
#1027=ORIENTED_EDGE('',*,*,#1026,.F.);
#1028=ORIENTED_EDGE('',*,*,#956,.F.);
#1029=DIRECTION('',(0.,0.,-1.));
#1030=VECTOR('',#1029,1.);
#1031=CARTESIAN_POINT('',(109.,18.,0.));
#1032=LINE('',#1031,#1030);
#1033=CARTESIAN_POINT('',(109.,18.,-58.));
#1034=VERTEX_POINT('',#1033);
#1035=EDGE_CURVE('E264',#947,#1034,#1032,.T.);
#1036=ORIENTED_EDGE('',*,*,#1035,.T.);
#1037=DIRECTION('',(1.,0.,0.));
#1038=VECTOR('',#1037,1.);
#1039=CARTESIAN_POINT('',(0.,18.,-58.));
#1040=LINE('',#1039,#1038);
#1041=CARTESIAN_POINT('',(51.,18.,-58.));
#1042=VERTEX_POINT('',#1041);
#1043=EDGE_CURVE('E257',#1042,#1034,#1040,.T.);
#1044=ORIENTED_EDGE('',*,*,#1043,.F.);
#1045=DIRECTION('',(0.,0.,-1.));
#1046=VECTOR('',#1045,1.);
#1047=CARTESIAN_POINT('',(51.,18.,0.));
#1048=LINE('',#1047,#1046);
#1049=EDGE_CURVE('E254',#931,#1042,#1048,.T.);
#1050=ORIENTED_EDGE('',*,*,#1049,.F.);
#1051=EDGE_LOOP('',(#987,#996,#1004,#1012,#1020,#1027,#1028,#1036,#1044,#1050));
#1052=FACE_BOUND('',#1051,.T.);
#1053=ADVANCED_FACE('F798',(#1052),#986,.F.);
#1054=CARTESIAN_POINT('',(156.,22.,-89.));
#1055=DIRECTION('',(-1.,0.,0.));
#1056=DIRECTION('',(0.,0.,1.));
#1057=AXIS2_PLACEMENT_3D('',#1054,#1055,#1056);
#1058=PLANE('',#1057);
#1059=ORIENTED_EDGE('',*,*,#1019,.T.);
#1060=DIRECTION('',(0.,-1.,0.));
#1061=VECTOR('',#1060,1.);
#1062=CARTESIAN_POINT('',(156.,22.,-85.));
#1063=LINE('',#1062,#1061);
#1064=EDGE_CURVE('E286',#1010,#715,#1063,.T.);
#1065=ORIENTED_EDGE('',*,*,#1064,.T.);
#1066=ORIENTED_EDGE('',*,*,#716,.F.);
#1067=DIRECTION('',(0.,1.,0.));
#1068=VECTOR('',#1067,1.);
#1069=CARTESIAN_POINT('',(156.,22.,-20.));
#1070=LINE('',#1069,#1068);
#1071=EDGE_CURVE('E283',#1018,#705,#1070,.F.);
#1072=ORIENTED_EDGE('',*,*,#1071,.F.);
#1073=EDGE_LOOP('',(#1059,#1065,#1066,#1072));
#1074=FACE_BOUND('',#1073,.T.);
#1075=ADVANCED_FACE('F807',(#1074),#1058,.T.);
#1076=CARTESIAN_POINT('',(0.,22.,-85.));
#1077=DIRECTION('',(0.,0.,1.));
#1078=DIRECTION('',(1.,0.,0.));
#1079=AXIS2_PLACEMENT_3D('',#1076,#1077,#1078);
#1080=PLANE('',#1079);
#1081=ORIENTED_EDGE('',*,*,#724,.F.);
#1082=ORIENTED_EDGE('',*,*,#1064,.F.);
#1083=ORIENTED_EDGE('',*,*,#1011,.T.);
#1084=DIRECTION('',(0.,-1.,0.));
#1085=VECTOR('',#1084,1.);
#1086=CARTESIAN_POINT('',(4.,22.,-85.));
#1087=LINE('',#1086,#1085);
#1088=EDGE_CURVE('E289',#1002,#723,#1087,.T.);
#1089=ORIENTED_EDGE('',*,*,#1088,.T.);
#1090=EDGE_LOOP('',(#1081,#1082,#1083,#1089));
#1091=FACE_BOUND('',#1090,.T.);
#1092=ADVANCED_FACE('F817',(#1091),#1080,.T.);
#1093=CARTESIAN_POINT('',(4.,22.,0.));
#1094=DIRECTION('',(1.,0.,0.));
#1095=DIRECTION('',(0.,0.,-1.));
#1096=AXIS2_PLACEMENT_3D('',#1093,#1094,#1095);
#1097=PLANE('',#1096);
#1098=ORIENTED_EDGE('',*,*,#732,.F.);
#1099=ORIENTED_EDGE('',*,*,#1088,.F.);
#1100=ORIENTED_EDGE('',*,*,#1003,.T.);
#1101=DIRECTION('',(0.,1.,0.));
#1102=VECTOR('',#1101,1.);
#1103=CARTESIAN_POINT('',(4.,22.,-20.));
#1104=LINE('',#1103,#1102);
#1105=EDGE_CURVE('E270',#731,#994,#1104,.T.);
#1106=ORIENTED_EDGE('',*,*,#1105,.F.);
#1107=EDGE_LOOP('',(#1098,#1099,#1100,#1106));
#1108=FACE_BOUND('',#1107,.T.);
#1109=ADVANCED_FACE('F827',(#1108),#1097,.T.);
#1110=CARTESIAN_POINT('',(140.,22.,-20.));
#1111=DIRECTION('',(0.,-1.,0.));
#1112=DIRECTION('',(0.,0.,-1.));
#1113=AXIS2_PLACEMENT_3D('',#1110,#1111,#1112);
#1114=CYLINDRICAL_SURFACE('',#1113,16.);
#1115=ORIENTED_EDGE('',*,*,#1026,.T.);
#1116=ORIENTED_EDGE('',*,*,#1071,.T.);
#1117=ORIENTED_EDGE('',*,*,#708,.T.);
#1118=ORIENTED_EDGE('',*,*,#962,.T.);
#1119=EDGE_LOOP('',(#1115,#1116,#1117,#1118));
#1120=FACE_BOUND('',#1119,.T.);
#1121=ADVANCED_FACE('F837',(#1120),#1114,.F.);
#1122=CARTESIAN_POINT('',(20.,22.,-20.));
#1123=DIRECTION('',(0.,-1.,0.));
#1124=DIRECTION('',(0.,0.,-1.));
#1125=AXIS2_PLACEMENT_3D('',#1122,#1123,#1124);
#1126=CYLINDRICAL_SURFACE('',#1125,16.);
#1127=ORIENTED_EDGE('',*,*,#995,.T.);
#1128=ORIENTED_EDGE('',*,*,#971,.T.);
#1129=ORIENTED_EDGE('',*,*,#741,.T.);
#1130=ORIENTED_EDGE('',*,*,#1105,.T.);
#1131=EDGE_LOOP('',(#1127,#1128,#1129,#1130));
#1132=FACE_BOUND('',#1131,.T.);
#1133=ADVANCED_FACE('F847',(#1132),#1126,.F.);
#1134=CARTESIAN_POINT('',(51.,12.,0.));
#1135=DIRECTION('',(1.,0.,0.));
#1136=DIRECTION('',(0.,0.,-1.));
#1137=AXIS2_PLACEMENT_3D('',#1134,#1135,#1136);
#1138=PLANE('',#1137);
#1139=ORIENTED_EDGE('',*,*,#1049,.T.);
#1140=DIRECTION('',(0.,1.,0.));
#1141=VECTOR('',#1140,1.);
#1142=CARTESIAN_POINT('',(51.,12.,-58.));
#1143=LINE('',#1142,#1141);
#1144=CARTESIAN_POINT('',(51.,8.,-58.));
#1145=VERTEX_POINT('',#1144);
#1146=EDGE_CURVE('E241',#1145,#1042,#1143,.T.);
#1147=ORIENTED_EDGE('',*,*,#1146,.F.);
#1148=DIRECTION('',(0.,0.,-1.));
#1149=VECTOR('',#1148,1.);
#1150=CARTESIAN_POINT('',(51.,8.,0.));
#1151=LINE('',#1150,#1149);
#1152=EDGE_CURVE('E244',#929,#1145,#1151,.T.);
#1153=ORIENTED_EDGE('',*,*,#1152,.F.);
#1154=ORIENTED_EDGE('',*,*,#932,.T.);
#1155=EDGE_LOOP('',(#1139,#1147,#1153,#1154));
#1156=FACE_BOUND('',#1155,.T.);
#1157=ADVANCED_FACE('F245',(#1156),#1138,.F.);
#1158=CARTESIAN_POINT('',(55.,12.,-58.));
#1159=DIRECTION('',(0.,0.,1.));
#1160=DIRECTION('',(1.,0.,0.));
#1161=AXIS2_PLACEMENT_3D('',#1158,#1159,#1160);
#1162=PLANE('',#1161);
#1163=ORIENTED_EDGE('',*,*,#1043,.T.);
#1164=DIRECTION('',(0.,1.,0.));
#1165=VECTOR('',#1164,1.);
#1166=CARTESIAN_POINT('',(109.,12.,-58.));
#1167=LINE('',#1166,#1165);
#1168=CARTESIAN_POINT('',(109.,8.,-58.));
#1169=VERTEX_POINT('',#1168);
#1170=EDGE_CURVE('E295',#1169,#1034,#1167,.T.);
#1171=ORIENTED_EDGE('',*,*,#1170,.F.);
#1172=DIRECTION('',(1.,0.,0.));
#1173=VECTOR('',#1172,1.);
#1174=CARTESIAN_POINT('',(0.,8.,-58.));
#1175=LINE('',#1174,#1173);
#1176=EDGE_CURVE('E249',#1145,#1169,#1175,.T.);
#1177=ORIENTED_EDGE('',*,*,#1176,.F.);
#1178=ORIENTED_EDGE('',*,*,#1146,.T.);
#1179=EDGE_LOOP('',(#1163,#1171,#1177,#1178));
#1180=FACE_BOUND('',#1179,.T.);
#1181=ADVANCED_FACE('F866',(#1180),#1162,.F.);
#1182=CARTESIAN_POINT('',(109.,12.,0.));
#1183=DIRECTION('',(1.,0.,0.));
#1184=DIRECTION('',(0.,0.,-1.));
#1185=AXIS2_PLACEMENT_3D('',#1182,#1183,#1184);
#1186=PLANE('',#1185);
#1187=ORIENTED_EDGE('',*,*,#1035,.F.);
#1188=ORIENTED_EDGE('',*,*,#948,.F.);
#1189=DIRECTION('',(0.,0.,-1.));
#1190=VECTOR('',#1189,1.);
#1191=CARTESIAN_POINT('',(109.,8.,0.));
#1192=LINE('',#1191,#1190);
#1193=EDGE_CURVE('E253',#939,#1169,#1192,.T.);
#1194=ORIENTED_EDGE('',*,*,#1193,.T.);
#1195=ORIENTED_EDGE('',*,*,#1170,.T.);
#1196=EDGE_LOOP('',(#1187,#1188,#1194,#1195));
#1197=FACE_BOUND('',#1196,.T.);
#1198=ADVANCED_FACE('F875',(#1197),#1186,.T.);
#1199=CARTESIAN_POINT('',(0.,8.,0.));
#1200=DIRECTION('',(0.,1.,0.));
#1201=DIRECTION('',(0.,0.,1.));
#1202=AXIS2_PLACEMENT_3D('',#1199,#1200,#1201);
#1203=PLANE('',#1202);
#1204=CARTESIAN_POINT('',(80.,8.,-17.));
#1205=DIRECTION('',(0.,1.,0.));
#1206=DIRECTION('',(0.,0.,1.));
#1207=AXIS2_PLACEMENT_3D('',#1204,#1205,#1206);
#1208=CIRCLE('',#1207,11.5);
#1209=CARTESIAN_POINT('',(80.,8.,-5.50000000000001));
#1210=VERTEX_POINT('',#1209);
#1211=EDGE_CURVE('E267',#1210,#1210,#1208,.T.);
#1212=ORIENTED_EDGE('',*,*,#1211,.T.);
#1213=EDGE_LOOP('',(#1212));
#1214=FACE_BOUND('',#1213,.T.);
#1215=CARTESIAN_POINT('',(80.,8.,-42.));
#1216=DIRECTION('',(0.,1.,0.));
#1217=DIRECTION('',(0.,0.,1.));
#1218=AXIS2_PLACEMENT_3D('',#1215,#1216,#1217);
#1219=CIRCLE('',#1218,11.5);
#1220=CARTESIAN_POINT('',(80.,8.,-30.5));
#1221=VERTEX_POINT('',#1220);
#1222=EDGE_CURVE('E300',#1221,#1221,#1219,.T.);
#1223=ORIENTED_EDGE('',*,*,#1222,.T.);
#1224=EDGE_LOOP('',(#1223));
#1225=FACE_BOUND('',#1224,.T.);
#1226=ORIENTED_EDGE('',*,*,#940,.F.);
#1227=ORIENTED_EDGE('',*,*,#1152,.T.);
#1228=ORIENTED_EDGE('',*,*,#1176,.T.);
#1229=ORIENTED_EDGE('',*,*,#1193,.F.);
#1230=EDGE_LOOP('',(#1226,#1227,#1228,#1229));
#1231=FACE_BOUND('',#1230,.T.);
#1232=ADVANCED_FACE('F251',(#1214,#1225,#1231),#1203,.F.);
#1233=CARTESIAN_POINT('',(80.,0.,-42.));
#1234=DIRECTION('',(0.,1.,0.));
#1235=DIRECTION('',(0.,0.,1.));
#1236=AXIS2_PLACEMENT_3D('',#1233,#1234,#1235);
#1237=CYLINDRICAL_SURFACE('',#1236,11.5);
#1238=ORIENTED_EDGE('',*,*,#1222,.F.);
#1239=EDGE_LOOP('',(#1238));
#1240=FACE_BOUND('',#1239,.T.);
#1241=ORIENTED_EDGE('',*,*,#545,.T.);
#1242=EDGE_LOOP('',(#1241));
#1243=FACE_BOUND('',#1242,.T.);
#1244=ADVANCED_FACE('F894',(#1240,#1243),#1237,.T.);
#1245=CARTESIAN_POINT('',(80.,0.,-17.));
#1246=DIRECTION('',(0.,1.,0.));
#1247=DIRECTION('',(0.,0.,1.));
#1248=AXIS2_PLACEMENT_3D('',#1245,#1246,#1247);
#1249=CYLINDRICAL_SURFACE('',#1248,11.5);
#1250=ORIENTED_EDGE('',*,*,#1211,.F.);
#1251=EDGE_LOOP('',(#1250));
#1252=FACE_BOUND('',#1251,.T.);
#1253=ORIENTED_EDGE('',*,*,#522,.T.);
#1254=EDGE_LOOP('',(#1253));
#1255=FACE_BOUND('',#1254,.T.);
#1256=ADVANCED_FACE('F904',(#1252,#1255),#1249,.T.);
#1257=CLOSED_SHELL('',(#174,#214,#236,#276,#300,#325,#370,#398,#422,#447,#464,#486,#498,#526,
#549,#617,#673,#698,#771,#783,#795,#819,#843,#860,#894,#906,#918,#981,#1053,#1075,#1092,#1109,
#1121,#1133,#1157,#1181,#1198,#1232,#1244,#1256));
#1258=MANIFOLD_SOLID_BREP('B2',#1257);
#1259=ADVANCED_BREP_SHAPE_REPRESENTATION('',(#18,#1258),#14);
#1260=SHAPE_DEFINITION_REPRESENTATION(#9,#1259);
ENDSEC;
END-ISO-10303-21;
